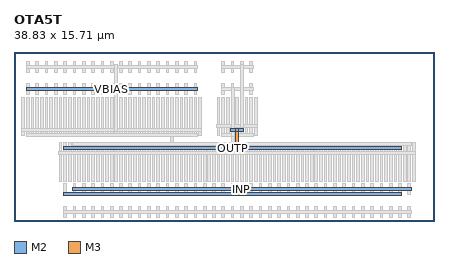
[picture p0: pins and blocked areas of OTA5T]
MACRO OTA5T
  ORIGIN 0 0 ;
  FOREIGN OTA5T 0 0 ;
  SIZE 38.83 BY 15.71 ;
  PIN OUTP
    DIRECTION INOUT ;
    USE SIGNAL ;
    PORT 
      LAYER M2 ;
        RECT 4.56 6.58 35.86 6.86 ;
      LAYER M2 ;
        RECT 20.04 8.26 21.24 8.54 ;
      LAYER M2 ;
        RECT 20.48 6.58 20.8 6.86 ;
      LAYER M3 ;
        RECT 20.5 6.72 20.78 8.4 ;
      LAYER M2 ;
        RECT 20.48 8.26 20.8 8.54 ;
    END
  END OUTP
  PIN INP
    DIRECTION INOUT ;
    USE SIGNAL ;
    PORT 
      LAYER M2 ;
        RECT 5.42 2.8 36.72 3.08 ;
    END
  END INP
  PIN INN
    DIRECTION INOUT ;
    USE SIGNAL ;
    PORT 
      LAYER M2 ;
        RECT 4.56 2.38 35.86 2.66 ;
    END
  END INN
  PIN VBIAS
    DIRECTION INOUT ;
    USE SIGNAL ;
    PORT 
      LAYER M2 ;
        RECT 1.12 12.04 16.94 12.32 ;
    END
  END VBIAS
  OBS 
  LAYER M2 ;
        RECT 5.42 7 36.72 7.28 ;
  LAYER M3 ;
        RECT 20.07 7.82 20.35 12.34 ;
  LAYER M2 ;
        RECT 20.05 7 20.37 7.28 ;
  LAYER M3 ;
        RECT 20.07 7.14 20.35 7.98 ;
  LAYER M2 ;
        RECT 20.05 7 20.37 7.28 ;
  LAYER M3 ;
        RECT 20.07 6.98 20.35 7.3 ;
  LAYER M2 ;
        RECT 20.05 7 20.37 7.28 ;
  LAYER M3 ;
        RECT 20.07 6.98 20.35 7.3 ;
  LAYER M2 ;
        RECT 1.12 7.84 16.94 8.12 ;
  LAYER M2 ;
        RECT 4.13 6.16 37.15 6.44 ;
  LAYER M2 ;
        RECT 14.46 7.84 14.78 8.12 ;
  LAYER M3 ;
        RECT 14.48 6.3 14.76 7.98 ;
  LAYER M2 ;
        RECT 14.46 6.16 14.78 6.44 ;
  LAYER M2 ;
        RECT 14.46 6.16 14.78 6.44 ;
  LAYER M3 ;
        RECT 14.48 6.14 14.76 6.46 ;
  LAYER M2 ;
        RECT 14.46 7.84 14.78 8.12 ;
  LAYER M3 ;
        RECT 14.48 7.82 14.76 8.14 ;
  LAYER M2 ;
        RECT 14.46 6.16 14.78 6.44 ;
  LAYER M3 ;
        RECT 14.48 6.14 14.76 6.46 ;
  LAYER M2 ;
        RECT 14.46 7.84 14.78 8.12 ;
  LAYER M3 ;
        RECT 14.48 7.82 14.76 8.14 ;
  LAYER M1 ;
        RECT 19.225 7.895 19.475 11.425 ;
  LAYER M1 ;
        RECT 19.225 11.675 19.475 12.685 ;
  LAYER M1 ;
        RECT 19.225 13.775 19.475 14.785 ;
  LAYER M1 ;
        RECT 18.795 7.895 19.045 11.425 ;
  LAYER M1 ;
        RECT 19.655 7.895 19.905 11.425 ;
  LAYER M1 ;
        RECT 20.085 7.895 20.335 11.425 ;
  LAYER M1 ;
        RECT 20.085 11.675 20.335 12.685 ;
  LAYER M1 ;
        RECT 20.085 13.775 20.335 14.785 ;
  LAYER M1 ;
        RECT 20.515 7.895 20.765 11.425 ;
  LAYER M1 ;
        RECT 20.945 7.895 21.195 11.425 ;
  LAYER M1 ;
        RECT 20.945 11.675 21.195 12.685 ;
  LAYER M1 ;
        RECT 20.945 13.775 21.195 14.785 ;
  LAYER M1 ;
        RECT 21.375 7.895 21.625 11.425 ;
  LAYER M1 ;
        RECT 21.805 7.895 22.055 11.425 ;
  LAYER M1 ;
        RECT 21.805 11.675 22.055 12.685 ;
  LAYER M1 ;
        RECT 21.805 13.775 22.055 14.785 ;
  LAYER M1 ;
        RECT 22.235 7.895 22.485 11.425 ;
  LAYER M2 ;
        RECT 19.18 12.04 22.1 12.32 ;
  LAYER M2 ;
        RECT 19.18 7.84 22.1 8.12 ;
  LAYER M2 ;
        RECT 19.18 14.14 22.1 14.42 ;
  LAYER M2 ;
        RECT 18.75 8.68 22.53 8.96 ;
  LAYER M3 ;
        RECT 20.07 7.82 20.35 12.34 ;
  LAYER M2 ;
        RECT 20.04 8.26 21.24 8.54 ;
  LAYER M3 ;
        RECT 20.93 8.66 21.21 14.44 ;
  LAYER M1 ;
        RECT 36.425 3.695 36.675 7.225 ;
  LAYER M1 ;
        RECT 36.425 2.435 36.675 3.445 ;
  LAYER M1 ;
        RECT 36.425 0.335 36.675 1.345 ;
  LAYER M1 ;
        RECT 36.855 3.695 37.105 7.225 ;
  LAYER M1 ;
        RECT 35.995 3.695 36.245 7.225 ;
  LAYER M1 ;
        RECT 35.565 3.695 35.815 7.225 ;
  LAYER M1 ;
        RECT 35.565 2.435 35.815 3.445 ;
  LAYER M1 ;
        RECT 35.565 0.335 35.815 1.345 ;
  LAYER M1 ;
        RECT 35.135 3.695 35.385 7.225 ;
  LAYER M1 ;
        RECT 34.705 3.695 34.955 7.225 ;
  LAYER M1 ;
        RECT 34.705 2.435 34.955 3.445 ;
  LAYER M1 ;
        RECT 34.705 0.335 34.955 1.345 ;
  LAYER M1 ;
        RECT 34.275 3.695 34.525 7.225 ;
  LAYER M1 ;
        RECT 33.845 3.695 34.095 7.225 ;
  LAYER M1 ;
        RECT 33.845 2.435 34.095 3.445 ;
  LAYER M1 ;
        RECT 33.845 0.335 34.095 1.345 ;
  LAYER M1 ;
        RECT 33.415 3.695 33.665 7.225 ;
  LAYER M1 ;
        RECT 32.985 3.695 33.235 7.225 ;
  LAYER M1 ;
        RECT 32.985 2.435 33.235 3.445 ;
  LAYER M1 ;
        RECT 32.985 0.335 33.235 1.345 ;
  LAYER M1 ;
        RECT 32.555 3.695 32.805 7.225 ;
  LAYER M1 ;
        RECT 32.125 3.695 32.375 7.225 ;
  LAYER M1 ;
        RECT 32.125 2.435 32.375 3.445 ;
  LAYER M1 ;
        RECT 32.125 0.335 32.375 1.345 ;
  LAYER M1 ;
        RECT 31.695 3.695 31.945 7.225 ;
  LAYER M1 ;
        RECT 31.265 3.695 31.515 7.225 ;
  LAYER M1 ;
        RECT 31.265 2.435 31.515 3.445 ;
  LAYER M1 ;
        RECT 31.265 0.335 31.515 1.345 ;
  LAYER M1 ;
        RECT 30.835 3.695 31.085 7.225 ;
  LAYER M1 ;
        RECT 30.405 3.695 30.655 7.225 ;
  LAYER M1 ;
        RECT 30.405 2.435 30.655 3.445 ;
  LAYER M1 ;
        RECT 30.405 0.335 30.655 1.345 ;
  LAYER M1 ;
        RECT 29.975 3.695 30.225 7.225 ;
  LAYER M1 ;
        RECT 29.545 3.695 29.795 7.225 ;
  LAYER M1 ;
        RECT 29.545 2.435 29.795 3.445 ;
  LAYER M1 ;
        RECT 29.545 0.335 29.795 1.345 ;
  LAYER M1 ;
        RECT 29.115 3.695 29.365 7.225 ;
  LAYER M1 ;
        RECT 28.685 3.695 28.935 7.225 ;
  LAYER M1 ;
        RECT 28.685 2.435 28.935 3.445 ;
  LAYER M1 ;
        RECT 28.685 0.335 28.935 1.345 ;
  LAYER M1 ;
        RECT 28.255 3.695 28.505 7.225 ;
  LAYER M1 ;
        RECT 27.825 3.695 28.075 7.225 ;
  LAYER M1 ;
        RECT 27.825 2.435 28.075 3.445 ;
  LAYER M1 ;
        RECT 27.825 0.335 28.075 1.345 ;
  LAYER M1 ;
        RECT 27.395 3.695 27.645 7.225 ;
  LAYER M1 ;
        RECT 26.965 3.695 27.215 7.225 ;
  LAYER M1 ;
        RECT 26.965 2.435 27.215 3.445 ;
  LAYER M1 ;
        RECT 26.965 0.335 27.215 1.345 ;
  LAYER M1 ;
        RECT 26.535 3.695 26.785 7.225 ;
  LAYER M1 ;
        RECT 26.105 3.695 26.355 7.225 ;
  LAYER M1 ;
        RECT 26.105 2.435 26.355 3.445 ;
  LAYER M1 ;
        RECT 26.105 0.335 26.355 1.345 ;
  LAYER M1 ;
        RECT 25.675 3.695 25.925 7.225 ;
  LAYER M1 ;
        RECT 25.245 3.695 25.495 7.225 ;
  LAYER M1 ;
        RECT 25.245 2.435 25.495 3.445 ;
  LAYER M1 ;
        RECT 25.245 0.335 25.495 1.345 ;
  LAYER M1 ;
        RECT 24.815 3.695 25.065 7.225 ;
  LAYER M1 ;
        RECT 24.385 3.695 24.635 7.225 ;
  LAYER M1 ;
        RECT 24.385 2.435 24.635 3.445 ;
  LAYER M1 ;
        RECT 24.385 0.335 24.635 1.345 ;
  LAYER M1 ;
        RECT 23.955 3.695 24.205 7.225 ;
  LAYER M1 ;
        RECT 23.525 3.695 23.775 7.225 ;
  LAYER M1 ;
        RECT 23.525 2.435 23.775 3.445 ;
  LAYER M1 ;
        RECT 23.525 0.335 23.775 1.345 ;
  LAYER M1 ;
        RECT 23.095 3.695 23.345 7.225 ;
  LAYER M1 ;
        RECT 22.665 3.695 22.915 7.225 ;
  LAYER M1 ;
        RECT 22.665 2.435 22.915 3.445 ;
  LAYER M1 ;
        RECT 22.665 0.335 22.915 1.345 ;
  LAYER M1 ;
        RECT 22.235 3.695 22.485 7.225 ;
  LAYER M1 ;
        RECT 21.805 3.695 22.055 7.225 ;
  LAYER M1 ;
        RECT 21.805 2.435 22.055 3.445 ;
  LAYER M1 ;
        RECT 21.805 0.335 22.055 1.345 ;
  LAYER M1 ;
        RECT 21.375 3.695 21.625 7.225 ;
  LAYER M1 ;
        RECT 20.945 3.695 21.195 7.225 ;
  LAYER M1 ;
        RECT 20.945 2.435 21.195 3.445 ;
  LAYER M1 ;
        RECT 20.945 0.335 21.195 1.345 ;
  LAYER M1 ;
        RECT 20.515 3.695 20.765 7.225 ;
  LAYER M1 ;
        RECT 20.085 3.695 20.335 7.225 ;
  LAYER M1 ;
        RECT 20.085 2.435 20.335 3.445 ;
  LAYER M1 ;
        RECT 20.085 0.335 20.335 1.345 ;
  LAYER M1 ;
        RECT 19.655 3.695 19.905 7.225 ;
  LAYER M1 ;
        RECT 19.225 3.695 19.475 7.225 ;
  LAYER M1 ;
        RECT 19.225 2.435 19.475 3.445 ;
  LAYER M1 ;
        RECT 19.225 0.335 19.475 1.345 ;
  LAYER M1 ;
        RECT 18.795 3.695 19.045 7.225 ;
  LAYER M1 ;
        RECT 18.365 3.695 18.615 7.225 ;
  LAYER M1 ;
        RECT 18.365 2.435 18.615 3.445 ;
  LAYER M1 ;
        RECT 18.365 0.335 18.615 1.345 ;
  LAYER M1 ;
        RECT 17.935 3.695 18.185 7.225 ;
  LAYER M1 ;
        RECT 17.505 3.695 17.755 7.225 ;
  LAYER M1 ;
        RECT 17.505 2.435 17.755 3.445 ;
  LAYER M1 ;
        RECT 17.505 0.335 17.755 1.345 ;
  LAYER M1 ;
        RECT 17.075 3.695 17.325 7.225 ;
  LAYER M1 ;
        RECT 16.645 3.695 16.895 7.225 ;
  LAYER M1 ;
        RECT 16.645 2.435 16.895 3.445 ;
  LAYER M1 ;
        RECT 16.645 0.335 16.895 1.345 ;
  LAYER M1 ;
        RECT 16.215 3.695 16.465 7.225 ;
  LAYER M1 ;
        RECT 15.785 3.695 16.035 7.225 ;
  LAYER M1 ;
        RECT 15.785 2.435 16.035 3.445 ;
  LAYER M1 ;
        RECT 15.785 0.335 16.035 1.345 ;
  LAYER M1 ;
        RECT 15.355 3.695 15.605 7.225 ;
  LAYER M1 ;
        RECT 14.925 3.695 15.175 7.225 ;
  LAYER M1 ;
        RECT 14.925 2.435 15.175 3.445 ;
  LAYER M1 ;
        RECT 14.925 0.335 15.175 1.345 ;
  LAYER M1 ;
        RECT 14.495 3.695 14.745 7.225 ;
  LAYER M1 ;
        RECT 14.065 3.695 14.315 7.225 ;
  LAYER M1 ;
        RECT 14.065 2.435 14.315 3.445 ;
  LAYER M1 ;
        RECT 14.065 0.335 14.315 1.345 ;
  LAYER M1 ;
        RECT 13.635 3.695 13.885 7.225 ;
  LAYER M1 ;
        RECT 13.205 3.695 13.455 7.225 ;
  LAYER M1 ;
        RECT 13.205 2.435 13.455 3.445 ;
  LAYER M1 ;
        RECT 13.205 0.335 13.455 1.345 ;
  LAYER M1 ;
        RECT 12.775 3.695 13.025 7.225 ;
  LAYER M1 ;
        RECT 12.345 3.695 12.595 7.225 ;
  LAYER M1 ;
        RECT 12.345 2.435 12.595 3.445 ;
  LAYER M1 ;
        RECT 12.345 0.335 12.595 1.345 ;
  LAYER M1 ;
        RECT 11.915 3.695 12.165 7.225 ;
  LAYER M1 ;
        RECT 11.485 3.695 11.735 7.225 ;
  LAYER M1 ;
        RECT 11.485 2.435 11.735 3.445 ;
  LAYER M1 ;
        RECT 11.485 0.335 11.735 1.345 ;
  LAYER M1 ;
        RECT 11.055 3.695 11.305 7.225 ;
  LAYER M1 ;
        RECT 10.625 3.695 10.875 7.225 ;
  LAYER M1 ;
        RECT 10.625 2.435 10.875 3.445 ;
  LAYER M1 ;
        RECT 10.625 0.335 10.875 1.345 ;
  LAYER M1 ;
        RECT 10.195 3.695 10.445 7.225 ;
  LAYER M1 ;
        RECT 9.765 3.695 10.015 7.225 ;
  LAYER M1 ;
        RECT 9.765 2.435 10.015 3.445 ;
  LAYER M1 ;
        RECT 9.765 0.335 10.015 1.345 ;
  LAYER M1 ;
        RECT 9.335 3.695 9.585 7.225 ;
  LAYER M1 ;
        RECT 8.905 3.695 9.155 7.225 ;
  LAYER M1 ;
        RECT 8.905 2.435 9.155 3.445 ;
  LAYER M1 ;
        RECT 8.905 0.335 9.155 1.345 ;
  LAYER M1 ;
        RECT 8.475 3.695 8.725 7.225 ;
  LAYER M1 ;
        RECT 8.045 3.695 8.295 7.225 ;
  LAYER M1 ;
        RECT 8.045 2.435 8.295 3.445 ;
  LAYER M1 ;
        RECT 8.045 0.335 8.295 1.345 ;
  LAYER M1 ;
        RECT 7.615 3.695 7.865 7.225 ;
  LAYER M1 ;
        RECT 7.185 3.695 7.435 7.225 ;
  LAYER M1 ;
        RECT 7.185 2.435 7.435 3.445 ;
  LAYER M1 ;
        RECT 7.185 0.335 7.435 1.345 ;
  LAYER M1 ;
        RECT 6.755 3.695 7.005 7.225 ;
  LAYER M1 ;
        RECT 6.325 3.695 6.575 7.225 ;
  LAYER M1 ;
        RECT 6.325 2.435 6.575 3.445 ;
  LAYER M1 ;
        RECT 6.325 0.335 6.575 1.345 ;
  LAYER M1 ;
        RECT 5.895 3.695 6.145 7.225 ;
  LAYER M1 ;
        RECT 5.465 3.695 5.715 7.225 ;
  LAYER M1 ;
        RECT 5.465 2.435 5.715 3.445 ;
  LAYER M1 ;
        RECT 5.465 0.335 5.715 1.345 ;
  LAYER M1 ;
        RECT 5.035 3.695 5.285 7.225 ;
  LAYER M1 ;
        RECT 4.605 3.695 4.855 7.225 ;
  LAYER M1 ;
        RECT 4.605 2.435 4.855 3.445 ;
  LAYER M1 ;
        RECT 4.605 0.335 4.855 1.345 ;
  LAYER M1 ;
        RECT 4.175 3.695 4.425 7.225 ;
  LAYER M2 ;
        RECT 4.56 0.7 36.72 0.98 ;
  LAYER M2 ;
        RECT 5.42 7 36.72 7.28 ;
  LAYER M2 ;
        RECT 4.56 6.58 35.86 6.86 ;
  LAYER M2 ;
        RECT 5.42 2.8 36.72 3.08 ;
  LAYER M2 ;
        RECT 4.56 2.38 35.86 2.66 ;
  LAYER M2 ;
        RECT 4.13 6.16 37.15 6.44 ;
  LAYER M1 ;
        RECT 1.165 7.895 1.415 11.425 ;
  LAYER M1 ;
        RECT 1.165 11.675 1.415 12.685 ;
  LAYER M1 ;
        RECT 1.165 13.775 1.415 14.785 ;
  LAYER M1 ;
        RECT 0.735 7.895 0.985 11.425 ;
  LAYER M1 ;
        RECT 1.595 7.895 1.845 11.425 ;
  LAYER M1 ;
        RECT 2.025 7.895 2.275 11.425 ;
  LAYER M1 ;
        RECT 2.025 11.675 2.275 12.685 ;
  LAYER M1 ;
        RECT 2.025 13.775 2.275 14.785 ;
  LAYER M1 ;
        RECT 2.455 7.895 2.705 11.425 ;
  LAYER M1 ;
        RECT 2.885 7.895 3.135 11.425 ;
  LAYER M1 ;
        RECT 2.885 11.675 3.135 12.685 ;
  LAYER M1 ;
        RECT 2.885 13.775 3.135 14.785 ;
  LAYER M1 ;
        RECT 3.315 7.895 3.565 11.425 ;
  LAYER M1 ;
        RECT 3.745 7.895 3.995 11.425 ;
  LAYER M1 ;
        RECT 3.745 11.675 3.995 12.685 ;
  LAYER M1 ;
        RECT 3.745 13.775 3.995 14.785 ;
  LAYER M1 ;
        RECT 4.175 7.895 4.425 11.425 ;
  LAYER M1 ;
        RECT 4.605 7.895 4.855 11.425 ;
  LAYER M1 ;
        RECT 4.605 11.675 4.855 12.685 ;
  LAYER M1 ;
        RECT 4.605 13.775 4.855 14.785 ;
  LAYER M1 ;
        RECT 5.035 7.895 5.285 11.425 ;
  LAYER M1 ;
        RECT 5.465 7.895 5.715 11.425 ;
  LAYER M1 ;
        RECT 5.465 11.675 5.715 12.685 ;
  LAYER M1 ;
        RECT 5.465 13.775 5.715 14.785 ;
  LAYER M1 ;
        RECT 5.895 7.895 6.145 11.425 ;
  LAYER M1 ;
        RECT 6.325 7.895 6.575 11.425 ;
  LAYER M1 ;
        RECT 6.325 11.675 6.575 12.685 ;
  LAYER M1 ;
        RECT 6.325 13.775 6.575 14.785 ;
  LAYER M1 ;
        RECT 6.755 7.895 7.005 11.425 ;
  LAYER M1 ;
        RECT 7.185 7.895 7.435 11.425 ;
  LAYER M1 ;
        RECT 7.185 11.675 7.435 12.685 ;
  LAYER M1 ;
        RECT 7.185 13.775 7.435 14.785 ;
  LAYER M1 ;
        RECT 7.615 7.895 7.865 11.425 ;
  LAYER M1 ;
        RECT 8.045 7.895 8.295 11.425 ;
  LAYER M1 ;
        RECT 8.045 11.675 8.295 12.685 ;
  LAYER M1 ;
        RECT 8.045 13.775 8.295 14.785 ;
  LAYER M1 ;
        RECT 8.475 7.895 8.725 11.425 ;
  LAYER M1 ;
        RECT 8.905 7.895 9.155 11.425 ;
  LAYER M1 ;
        RECT 8.905 11.675 9.155 12.685 ;
  LAYER M1 ;
        RECT 8.905 13.775 9.155 14.785 ;
  LAYER M1 ;
        RECT 9.335 7.895 9.585 11.425 ;
  LAYER M1 ;
        RECT 9.765 7.895 10.015 11.425 ;
  LAYER M1 ;
        RECT 9.765 11.675 10.015 12.685 ;
  LAYER M1 ;
        RECT 9.765 13.775 10.015 14.785 ;
  LAYER M1 ;
        RECT 10.195 7.895 10.445 11.425 ;
  LAYER M1 ;
        RECT 10.625 7.895 10.875 11.425 ;
  LAYER M1 ;
        RECT 10.625 11.675 10.875 12.685 ;
  LAYER M1 ;
        RECT 10.625 13.775 10.875 14.785 ;
  LAYER M1 ;
        RECT 11.055 7.895 11.305 11.425 ;
  LAYER M1 ;
        RECT 11.485 7.895 11.735 11.425 ;
  LAYER M1 ;
        RECT 11.485 11.675 11.735 12.685 ;
  LAYER M1 ;
        RECT 11.485 13.775 11.735 14.785 ;
  LAYER M1 ;
        RECT 11.915 7.895 12.165 11.425 ;
  LAYER M1 ;
        RECT 12.345 7.895 12.595 11.425 ;
  LAYER M1 ;
        RECT 12.345 11.675 12.595 12.685 ;
  LAYER M1 ;
        RECT 12.345 13.775 12.595 14.785 ;
  LAYER M1 ;
        RECT 12.775 7.895 13.025 11.425 ;
  LAYER M1 ;
        RECT 13.205 7.895 13.455 11.425 ;
  LAYER M1 ;
        RECT 13.205 11.675 13.455 12.685 ;
  LAYER M1 ;
        RECT 13.205 13.775 13.455 14.785 ;
  LAYER M1 ;
        RECT 13.635 7.895 13.885 11.425 ;
  LAYER M1 ;
        RECT 14.065 7.895 14.315 11.425 ;
  LAYER M1 ;
        RECT 14.065 11.675 14.315 12.685 ;
  LAYER M1 ;
        RECT 14.065 13.775 14.315 14.785 ;
  LAYER M1 ;
        RECT 14.495 7.895 14.745 11.425 ;
  LAYER M1 ;
        RECT 14.925 7.895 15.175 11.425 ;
  LAYER M1 ;
        RECT 14.925 11.675 15.175 12.685 ;
  LAYER M1 ;
        RECT 14.925 13.775 15.175 14.785 ;
  LAYER M1 ;
        RECT 15.355 7.895 15.605 11.425 ;
  LAYER M1 ;
        RECT 15.785 7.895 16.035 11.425 ;
  LAYER M1 ;
        RECT 15.785 11.675 16.035 12.685 ;
  LAYER M1 ;
        RECT 15.785 13.775 16.035 14.785 ;
  LAYER M1 ;
        RECT 16.215 7.895 16.465 11.425 ;
  LAYER M1 ;
        RECT 16.645 7.895 16.895 11.425 ;
  LAYER M1 ;
        RECT 16.645 11.675 16.895 12.685 ;
  LAYER M1 ;
        RECT 16.645 13.775 16.895 14.785 ;
  LAYER M1 ;
        RECT 17.075 7.895 17.325 11.425 ;
  LAYER M2 ;
        RECT 1.12 14.14 16.94 14.42 ;
  LAYER M2 ;
        RECT 0.69 8.26 17.37 8.54 ;
  LAYER M2 ;
        RECT 1.12 7.84 16.94 8.12 ;
  LAYER M2 ;
        RECT 1.12 12.04 16.94 12.32 ;
  LAYER M3 ;
        RECT 9.32 8.24 9.6 14.44 ;
  END 
END OTA5T
